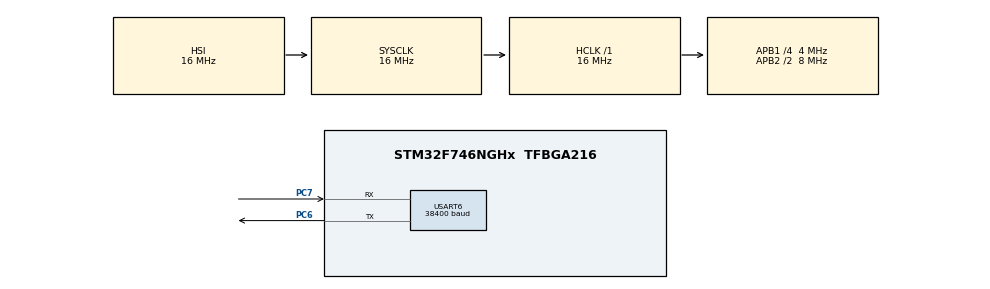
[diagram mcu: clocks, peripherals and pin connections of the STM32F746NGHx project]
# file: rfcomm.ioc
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Mcu.Family=STM32F7
Mcu.Name=STM32F746NGHx
Mcu.Package=TFBGA216
NVIC.PriorityGroup=NVIC_PRIORITYGROUP_4
PC6.Mode=Asynchronous
PC6.Signal=USART6_TX
PC7.Mode=Asynchronous
PC7.Signal=USART6_RX
ProjectManager.HeapSize=0x200
ProjectManager.StackSize=0x400
ProjectManager.TargetToolchain=MDK-ARM V5
RCC.AHBFreq_Value=16000000
RCC.APB1CLKDivider=RCC_HCLK_DIV4
RCC.APB1Freq_Value=4000000
RCC.APB1TimFreq_Value=8000000
RCC.APB2CLKDivider=RCC_HCLK_DIV2
RCC.APB2Freq_Value=8000000
RCC.APB2TimFreq_Value=16000000
RCC.CortexFreq_Value=16000000
RCC.HCLKFreq_Value=16000000
RCC.HSE_VALUE=25000000
RCC.HSI_VALUE=16000000
RCC.LSE_VALUE=32768
RCC.PLLM=10
RCC.PLLN=210
RCC.PLLSourceVirtual=RCC_PLLSOURCE_HSI
RCC.SYSCLKFreq_VALUE=16000000
RCC.USBFreq_Value=168000000
RCC.VCOOutputFreq_Value=336000000
USART6.BaudRate=38400
USART6.VirtualMode-Asynchronous=VM_ASYNC
USART6.WordLength=WORDLENGTH_8B
board=STM32F746G-DISCO

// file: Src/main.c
/**
  ******************************************************************************
  * @file           : main.c
  * @brief          : Main program body
  ******************************************************************************
  ** This notice applies to any and all portions of this file
  * that are not between comment pairs USER CODE BEGIN and
  * USER CODE END. Other portions of this file, whether
  * inserted by the user or by software development tools
  * are owned by their respective copyright owners.
  *
  * COPYRIGHT(c) 2018 STMicroelectronics
  *
  * Redistribution and use in source and binary forms, with or without modification,
  * are permitted provided that the following conditions are met:
  *   1. Redistributions of source code must retain the above copyright notice,
  *      this list of conditions and the following disclaimer.
  *   2. Redistributions in binary form must reproduce the above copyright notice,
  *      this list of conditions and the following disclaimer in the documentation
  *      and/or other materials provided with the distribution.
  *   3. Neither the name of STMicroelectronics nor the names of its contributors
  *      may be used to endorse or promote products derived from this software
  *      without specific prior written permission.
  *
  * THIS SOFTWARE IS PROVIDED BY THE COPYRIGHT HOLDERS AND CONTRIBUTORS "AS IS"
  * AND ANY EXPRESS OR IMPLIED WARRANTIES, INCLUDING, BUT NOT LIMITED TO, THE
  * IMPLIED WARRANTIES OF MERCHANTABILITY AND FITNESS FOR A PARTICULAR PURPOSE ARE
  * DISCLAIMED. IN NO EVENT SHALL THE COPYRIGHT HOLDER OR CONTRIBUTORS BE LIABLE
  * FOR ANY DIRECT, INDIRECT, INCIDENTAL, SPECIAL, EXEMPLARY, OR CONSEQUENTIAL
  * DAMAGES (INCLUDING, BUT NOT LIMITED TO, PROCUREMENT OF SUBSTITUTE GOODS OR
  * SERVICES; LOSS OF USE, DATA, OR PROFITS; OR BUSINESS INTERRUPTION) HOWEVER
  * CAUSED AND ON ANY THEORY OF LIABILITY, WHETHER IN CONTRACT, STRICT LIABILITY,
  * OR TORT (INCLUDING NEGLIGENCE OR OTHERWISE) ARISING IN ANY WAY OUT OF THE USE
  * OF THIS SOFTWARE, EVEN IF ADVISED OF THE POSSIBILITY OF SUCH DAMAGE.
  *
  ******************************************************************************
  */
#include "main.h"
#include "stm32f7xx_hal.h"

UART_HandleTypeDef huart6;

/* USER CODE BEGIN PV */
/* Private variables ---------------------------------------------------------*/

char ch[30] = "HELLO FROM ARM!\n";
/* USER CODE END PV */

void SystemClock_Config(void);
static void MX_GPIO_Init(void);
static void MX_USART6_UART_Init(void);

/* USER CODE BEGIN PFP */
/* Private function prototypes -----------------------------------------------*/

/* USER CODE END PFP */

int main(void)
{

  /* MCU Configuration----------------------------------------------------------*/

  /* Reset of all peripherals, Initializes the Flash interface and the Systick. */
  HAL_Init();

  /* Configure the system clock */
  SystemClock_Config();

  /* Initialize all configured peripherals */
  MX_GPIO_Init();
  MX_USART6_UART_Init();

  /* Infinite loop */
  while (1)
  {

		HAL_UART_Transmit(&huart6,(uint8_t *)&ch,16,0xFFFF);

		HAL_Delay(400);

  }

}

void SystemClock_Config(void)
{

  RCC_OscInitTypeDef RCC_OscInitStruct;
  RCC_ClkInitTypeDef RCC_ClkInitStruct;
  RCC_PeriphCLKInitTypeDef PeriphClkInitStruct;

    /**Configure the main internal regulator output voltage
    */
  __HAL_RCC_PWR_CLK_ENABLE();

  __HAL_PWR_VOLTAGESCALING_CONFIG(PWR_REGULATOR_VOLTAGE_SCALE3);

    /**Initializes the CPU, AHB and APB busses clocks
    */
  RCC_OscInitStruct.OscillatorType = RCC_OSCILLATORTYPE_HSI;
  RCC_OscInitStruct.HSIState = RCC_HSI_ON;
  RCC_OscInitStruct.HSICalibrationValue = 16;
  RCC_OscInitStruct.PLL.PLLState = RCC_PLL_NONE;
  if (HAL_RCC_OscConfig(&RCC_OscInitStruct) != HAL_OK)
  {
    _Error_Handler(__FILE__, __LINE__);
  }

    /**Initializes the CPU, AHB and APB busses clocks
    */
  RCC_ClkInitStruct.ClockType = RCC_CLOCKTYPE_HCLK|RCC_CLOCKTYPE_SYSCLK
                              |RCC_CLOCKTYPE_PCLK1|RCC_CLOCKTYPE_PCLK2;
  RCC_ClkInitStruct.SYSCLKSource = RCC_SYSCLKSOURCE_HSI;
  RCC_ClkInitStruct.AHBCLKDivider = RCC_SYSCLK_DIV1;
  RCC_ClkInitStruct.APB1CLKDivider = RCC_HCLK_DIV4;
  RCC_ClkInitStruct.APB2CLKDivider = RCC_HCLK_DIV2;

  if (HAL_RCC_ClockConfig(&RCC_ClkInitStruct, FLASH_LATENCY_0) != HAL_OK)
  {
    _Error_Handler(__FILE__, __LINE__);
  }

  PeriphClkInitStruct.PeriphClockSelection = RCC_PERIPHCLK_USART6;
  PeriphClkInitStruct.Usart6ClockSelection = RCC_USART6CLKSOURCE_PCLK2;
  if (HAL_RCCEx_PeriphCLKConfig(&PeriphClkInitStruct) != HAL_OK)
  {
    _Error_Handler(__FILE__, __LINE__);
  }

    /**Configure the Systick interrupt time
    */
  HAL_SYSTICK_Config(HAL_RCC_GetHCLKFreq()/1000);

    /**Configure the Systick
    */
  HAL_SYSTICK_CLKSourceConfig(SYSTICK_CLKSOURCE_HCLK);

  /* SysTick_IRQn interrupt configuration */
  HAL_NVIC_SetPriority(SysTick_IRQn, 0, 0);
}

/* USART6 init function */
static void MX_USART6_UART_Init(void)
{

  huart6.Instance = USART6;
  huart6.Init.BaudRate = 38400;
  huart6.Init.WordLength = UART_WORDLENGTH_8B;
  huart6.Init.StopBits = UART_STOPBITS_1;
  huart6.Init.Parity = UART_PARITY_NONE;
  huart6.Init.Mode = UART_MODE_TX_RX;
  huart6.Init.HwFlowCtl = UART_HWCONTROL_NONE;
  huart6.Init.OverSampling = UART_OVERSAMPLING_16;
  huart6.Init.OneBitSampling = UART_ONE_BIT_SAMPLE_DISABLE;
  huart6.AdvancedInit.AdvFeatureInit = UART_ADVFEATURE_NO_INIT;
  if (HAL_UART_Init(&huart6) != HAL_OK)
  {
    _Error_Handler(__FILE__, __LINE__);
  }

}

/** Pinout Configuration
*/
static void MX_GPIO_Init(void)
{

  /* GPIO Ports Clock Enable */
  __HAL_RCC_GPIOC_CLK_ENABLE();

	  GPIO_InitTypeDef GPIO_InitStruct;

  /* GPIO Ports Clock Enable */
  __HAL_RCC_GPIOA_CLK_ENABLE();
  __HAL_RCC_GPIOI_CLK_ENABLE();
  __HAL_RCC_GPIOH_CLK_ENABLE();

  /*Configure GPIO pin Output Level */
  HAL_GPIO_WritePin(GPIOI, GPIO_PIN_1, GPIO_PIN_RESET);

  /*Configure GPIO pin : PI1 */
  GPIO_InitStruct.Pin = GPIO_PIN_1;
  GPIO_InitStruct.Mode = GPIO_MODE_OUTPUT_PP;
  GPIO_InitStruct.Pull = GPIO_NOPULL;
  GPIO_InitStruct.Speed = GPIO_SPEED_FREQ_LOW;
  HAL_GPIO_Init(GPIOI, &GPIO_InitStruct);

  /*Configure GPIO pin : PI11 */
  GPIO_InitStruct.Pin = GPIO_PIN_11;
  GPIO_InitStruct.Mode = GPIO_MODE_IT_RISING;
  GPIO_InitStruct.Pull = GPIO_NOPULL;
  HAL_GPIO_Init(GPIOI, &GPIO_InitStruct);

  /* EXTI interrupt init*/
  HAL_NVIC_SetPriority(EXTI15_10_IRQn, 1, 0);
  HAL_NVIC_EnableIRQ(EXTI15_10_IRQn);

}

void _Error_Handler(char *file, int line)
{
  while(1)
  {
  }
}

/************************ (C) COPYRIGHT STMicroelectronics *****END OF FILE****/
